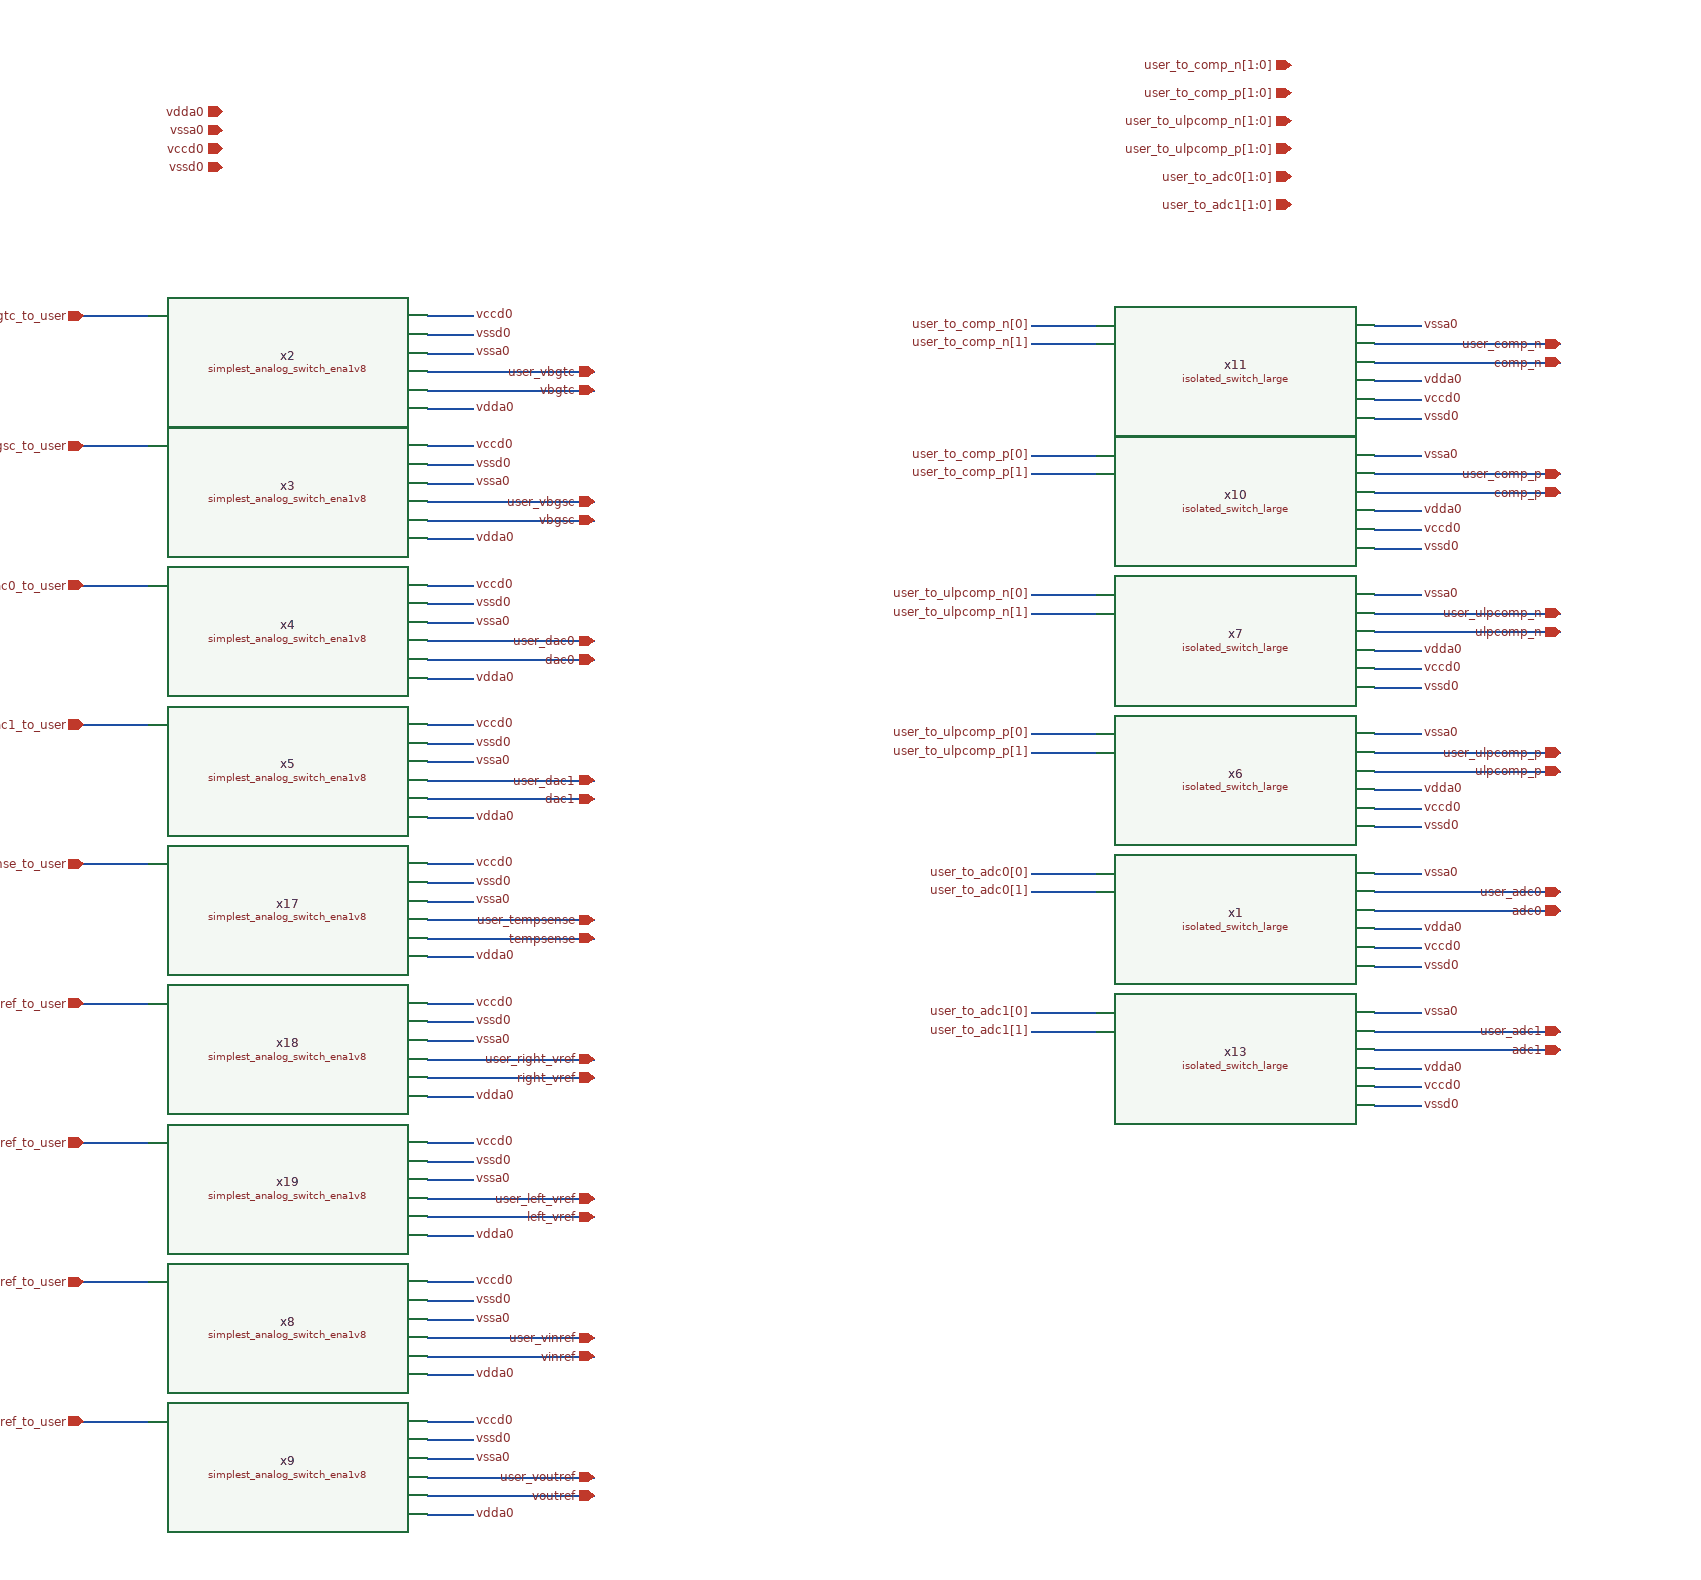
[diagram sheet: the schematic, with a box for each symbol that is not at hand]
v {xschem version=3.4.5 file_version=1.2
}
G {}
K {}
V {}
S {}
E {}
N -210 120 -140 120 {
lab=vbgtc_to_user}
N 160 120 210 120 {
lab=vccd0}
N 160 140 210 140 {
lab=vssd0}
N 160 160 210 160 {
lab=vssa0}
N 160 220 210 220 {
lab=vdda0}
N -210 260 -140 260 {
lab=vbgsc_to_user}
N 160 260 210 260 {
lab=vccd0}
N 160 280 210 280 {
lab=vssd0}
N 160 300 210 300 {
lab=vssa0}
N 160 360 210 360 {
lab=vdda0}
N -210 410 -140 410 {
lab=dac0_to_user}
N 160 410 210 410 {
lab=vccd0}
N 160 430 210 430 {
lab=vssd0}
N 160 450 210 450 {
lab=vssa0}
N 160 510 210 510 {
lab=vdda0}
N 160 180 340 180 {
lab=user_vbgtc}
N 160 320 340 320 {
lab=user_vbgsc}
N 160 470 340 470 {
lab=user_dac0}
N -210 560 -140 560 {
lab=dac1_to_user}
N 160 560 210 560 {
lab=vccd0}
N 160 580 210 580 {
lab=vssd0}
N 160 600 210 600 {
lab=vssa0}
N 160 660 210 660 {
lab=vdda0}
N 160 620 340 620 {
lab=user_dac1}
N 810 720 880 720 {
lab=user_to_adc0[0]}
N -210 1160 -140 1160 {
lab=vinref_to_user}
N 160 1160 210 1160 {
lab=vccd0}
N 160 1180 210 1180 {
lab=vssd0}
N 160 1200 210 1200 {
lab=vssa0}
N 160 1260 210 1260 {
lab=vdda0}
N 160 1220 340 1220 {
lab=user_vinref}
N -210 1310 -140 1310 {
lab=voutref_to_user}
N 160 1310 210 1310 {
lab=vccd0}
N 160 1330 210 1330 {
lab=vssd0}
N 160 1350 210 1350 {
lab=vssa0}
N 160 1410 210 1410 {
lab=vdda0}
N 160 1370 340 1370 {
lab=user_voutref}
N 810 130 880 130 {
lab=user_to_comp_n[0]}
N 1180 210 1230 210 {
lab=vccd0}
N 1180 230 1230 230 {
lab=vssd0}
N 1180 130 1230 130 {
lab=vssa0}
N 810 270 880 270 {
lab=user_to_comp_p[0]}
N 810 420 880 420 {
lab=user_to_ulpcomp_n[0]}
N 810 570 880 570 {
lab=user_to_ulpcomp_p[0]}
N -210 710 -140 710 {
lab=tempsense_to_user}
N 160 710 210 710 {
lab=vccd0}
N 160 730 210 730 {
lab=vssd0}
N 160 750 210 750 {
lab=vssa0}
N 160 810 210 810 {
lab=vdda0}
N 160 770 340 770 {
lab=user_tempsense}
N -210 860 -140 860 {
lab=right_vref_to_user}
N 160 860 210 860 {
lab=vccd0}
N 160 880 210 880 {
lab=vssd0}
N 160 900 210 900 {
lab=vssa0}
N 160 960 210 960 {
lab=vdda0}
N 160 920 340 920 {
lab=user_right_vref}
N -210 1010 -140 1010 {
lab=left_vref_to_user}
N 160 1010 210 1010 {
lab=vccd0}
N 160 1030 210 1030 {
lab=vssd0}
N 160 1050 210 1050 {
lab=vssa0}
N 160 1110 210 1110 {
lab=vdda0}
N 160 1070 340 1070 {
lab=user_left_vref}
N 810 870 880 870 {
lab=user_to_adc1[0]}
N 810 890 880 890 {
lab=user_to_adc1[1]}
N 810 740 880 740 {
lab=user_to_adc0[1]}
N 810 590 880 590 {
lab=user_to_ulpcomp_p[1]}
N 810 440 880 440 {
lab=user_to_ulpcomp_n[1]}
N 810 290 880 290 {
lab=user_to_comp_p[1]}
N 810 150 880 150 {
lab=user_to_comp_n[1]}
N 1180 190 1230 190 {
lab=vdda0}
N 1180 350 1230 350 {
lab=vccd0}
N 1180 370 1230 370 {
lab=vssd0}
N 1180 270 1230 270 {
lab=vssa0}
N 1180 330 1230 330 {
lab=vdda0}
N 1180 500 1230 500 {
lab=vccd0}
N 1180 520 1230 520 {
lab=vssd0}
N 1180 420 1230 420 {
lab=vssa0}
N 1180 480 1230 480 {
lab=vdda0}
N 1180 650 1230 650 {
lab=vccd0}
N 1180 670 1230 670 {
lab=vssd0}
N 1180 570 1230 570 {
lab=vssa0}
N 1180 630 1230 630 {
lab=vdda0}
N 1180 800 1230 800 {
lab=vccd0}
N 1180 820 1230 820 {
lab=vssd0}
N 1180 720 1230 720 {
lab=vssa0}
N 1180 780 1230 780 {
lab=vdda0}
N 1180 950 1230 950 {
lab=vccd0}
N 1180 970 1230 970 {
lab=vssd0}
N 1180 870 1230 870 {
lab=vssa0}
N 1180 930 1230 930 {
lab=vdda0}
N 160 1390 340 1390 {
lab=voutref}
N 160 1240 340 1240 {
lab=vinref}
N 160 1090 340 1090 {
lab=left_vref}
N 160 940 340 940 {
lab=right_vref}
N 160 790 340 790 {
lab=tempsense}
N 160 640 340 640 {
lab=dac1}
N 160 490 340 490 {
lab=dac0}
N 160 340 340 340 {
lab=vbgsc}
N 160 200 340 200 {
lab=vbgtc}
N 1180 460 1380 460 {
lab=ulpcomp_n}
N 1180 610 1380 610 {
lab=ulpcomp_p}
N 1180 760 1380 760 {
lab=adc0}
N 1180 910 1380 910 {
lab=adc1}
N 1180 310 1380 310 {
lab=comp_p}
N 1180 170 1380 170 {
lab=comp_n}
N 1180 890 1380 890 {
lab=user_adc1}
N 1180 740 1380 740 {
lab=user_adc0}
N 1180 590 1380 590 {
lab=user_ulpcomp_p}
N 1180 440 1380 440 {
lab=user_ulpcomp_n}
N 1180 290 1380 290 {
lab=user_comp_p}
N 1180 150 1380 150 {
lab=user_comp_n}
C {devices/iopin.sym} -60 -60 0 0 {name=p1 lab=vccd0}
C {devices/iopin.sym} -60 -100 0 0 {name=p3 lab=vdda0}
C {devices/iopin.sym} -60 -80 0 0 {name=p4 lab=vssa0}
C {devices/iopin.sym} -60 -40 0 0 {name=p5 lab=vssd0}
C {simplest_analog_switch_ena1v8.sym} 10 170 0 0 {name=x2}
C {devices/ipin.sym} -210 120 0 0 {name=p10 lab=vbgtc_to_user}
C {devices/lab_pin.sym} 210 120 0 1 {name=p11 sig_type=std_logic lab=vccd0}
C {devices/lab_pin.sym} 210 140 0 1 {name=p12 sig_type=std_logic lab=vssd0}
C {devices/lab_pin.sym} 210 160 0 1 {name=p13 sig_type=std_logic lab=vssa0}
C {devices/lab_pin.sym} 210 220 0 1 {name=p14 sig_type=std_logic lab=vdda0}
C {simplest_analog_switch_ena1v8.sym} 10 310 0 0 {name=x3}
C {devices/ipin.sym} -210 260 0 0 {name=p15 lab=vbgsc_to_user}
C {devices/lab_pin.sym} 210 260 0 1 {name=p16 sig_type=std_logic lab=vccd0}
C {devices/lab_pin.sym} 210 280 0 1 {name=p17 sig_type=std_logic lab=vssd0}
C {devices/lab_pin.sym} 210 300 0 1 {name=p18 sig_type=std_logic lab=vssa0}
C {devices/lab_pin.sym} 210 360 0 1 {name=p19 sig_type=std_logic lab=vdda0}
C {simplest_analog_switch_ena1v8.sym} 10 460 0 0 {name=x4}
C {devices/ipin.sym} -210 410 0 0 {name=p20 lab=dac0_to_user}
C {devices/lab_pin.sym} 210 410 0 1 {name=p21 sig_type=std_logic lab=vccd0}
C {devices/lab_pin.sym} 210 430 0 1 {name=p22 sig_type=std_logic lab=vssd0}
C {devices/lab_pin.sym} 210 450 0 1 {name=p23 sig_type=std_logic lab=vssa0}
C {devices/lab_pin.sym} 210 510 0 1 {name=p24 sig_type=std_logic lab=vdda0}
C {simplest_analog_switch_ena1v8.sym} 10 610 0 0 {name=x5}
C {devices/ipin.sym} -210 560 0 0 {name=p25 lab=dac1_to_user}
C {devices/lab_pin.sym} 210 560 0 1 {name=p26 sig_type=std_logic lab=vccd0}
C {devices/lab_pin.sym} 210 580 0 1 {name=p27 sig_type=std_logic lab=vssd0}
C {devices/lab_pin.sym} 210 600 0 1 {name=p28 sig_type=std_logic lab=vssa0}
C {devices/lab_pin.sym} 210 660 0 1 {name=p29 sig_type=std_logic lab=vdda0}
C {simplest_analog_switch_ena1v8.sym} 10 1210 0 0 {name=x8}
C {devices/ipin.sym} -210 1160 0 0 {name=p40 lab=vinref_to_user}
C {devices/lab_pin.sym} 210 1160 0 1 {name=p41 sig_type=std_logic lab=vccd0}
C {devices/lab_pin.sym} 210 1180 0 1 {name=p42 sig_type=std_logic lab=vssd0}
C {devices/lab_pin.sym} 210 1200 0 1 {name=p43 sig_type=std_logic lab=vssa0}
C {devices/lab_pin.sym} 210 1260 0 1 {name=p44 sig_type=std_logic lab=vdda0}
C {simplest_analog_switch_ena1v8.sym} 10 1360 0 0 {name=x9}
C {devices/ipin.sym} -210 1310 0 0 {name=p45 lab=voutref_to_user}
C {devices/lab_pin.sym} 210 1310 0 1 {name=p46 sig_type=std_logic lab=vccd0}
C {devices/lab_pin.sym} 210 1330 0 1 {name=p47 sig_type=std_logic lab=vssd0}
C {devices/lab_pin.sym} 210 1350 0 1 {name=p48 sig_type=std_logic lab=vssa0}
C {devices/lab_pin.sym} 210 1410 0 1 {name=p49 sig_type=std_logic lab=vdda0}
C {devices/lab_pin.sym} 1230 210 0 1 {name=p62 sig_type=std_logic lab=vccd0}
C {devices/lab_pin.sym} 1230 230 0 1 {name=p63 sig_type=std_logic lab=vssd0}
C {devices/lab_pin.sym} 1230 130 0 1 {name=p64 sig_type=std_logic lab=vssa0}
C {simplest_analog_switch_ena1v8.sym} 10 760 0 0 {name=x17}
C {devices/ipin.sym} -210 710 0 0 {name=p86 lab=tempsense_to_user}
C {devices/lab_pin.sym} 210 710 0 1 {name=p87 sig_type=std_logic lab=vccd0}
C {devices/lab_pin.sym} 210 730 0 1 {name=p88 sig_type=std_logic lab=vssd0}
C {devices/lab_pin.sym} 210 750 0 1 {name=p89 sig_type=std_logic lab=vssa0}
C {devices/lab_pin.sym} 210 810 0 1 {name=p90 sig_type=std_logic lab=vdda0}
C {simplest_analog_switch_ena1v8.sym} 10 910 0 0 {name=x18}
C {devices/ipin.sym} -210 860 0 0 {name=p91 lab=right_vref_to_user}
C {devices/lab_pin.sym} 210 860 0 1 {name=p92 sig_type=std_logic lab=vccd0}
C {devices/lab_pin.sym} 210 880 0 1 {name=p93 sig_type=std_logic lab=vssd0}
C {devices/lab_pin.sym} 210 900 0 1 {name=p94 sig_type=std_logic lab=vssa0}
C {devices/lab_pin.sym} 210 960 0 1 {name=p95 sig_type=std_logic lab=vdda0}
C {simplest_analog_switch_ena1v8.sym} 10 1060 0 0 {name=x19}
C {devices/ipin.sym} -210 1010 0 0 {name=p96 lab=left_vref_to_user}
C {devices/lab_pin.sym} 210 1010 0 1 {name=p97 sig_type=std_logic lab=vccd0}
C {devices/lab_pin.sym} 210 1030 0 1 {name=p98 sig_type=std_logic lab=vssd0}
C {devices/lab_pin.sym} 210 1050 0 1 {name=p99 sig_type=std_logic lab=vssa0}
C {devices/lab_pin.sym} 210 1110 0 1 {name=p100 sig_type=std_logic lab=vdda0}
C {devices/iopin.sym} 1380 610 0 0 {name=p181 lab=ulpcomp_p}
C {devices/iopin.sym} 1380 460 0 0 {name=p182 lab=ulpcomp_n}
C {devices/iopin.sym} 1380 310 0 0 {name=p183 lab=comp_p}
C {devices/iopin.sym} 1380 170 0 0 {name=p184 lab=comp_n}
C {devices/iopin.sym} 1380 760 0 0 {name=p185 lab=adc0}
C {devices/iopin.sym} 1380 910 0 0 {name=p186 lab=adc1}
C {devices/iopin.sym} 340 490 0 0 {name=p187 lab=dac0}
C {devices/iopin.sym} 340 640 0 0 {name=p188 lab=dac1}
C {devices/lab_pin.sym} 810 130 0 0 {name=p31 sig_type=std_logic lab=user_to_comp_n[0]}
C {devices/lab_pin.sym} 810 150 0 0 {name=p32 sig_type=std_logic lab=user_to_comp_n[1]}
C {devices/lab_pin.sym} 810 270 0 0 {name=p33 sig_type=std_logic lab=user_to_comp_p[0]}
C {devices/lab_pin.sym} 810 290 0 0 {name=p34 sig_type=std_logic lab=user_to_comp_p[1]}
C {devices/lab_pin.sym} 810 420 0 0 {name=p35 sig_type=std_logic lab=user_to_ulpcomp_n[0]}
C {devices/lab_pin.sym} 810 440 0 0 {name=p50 sig_type=std_logic lab=user_to_ulpcomp_n[1]}
C {devices/lab_pin.sym} 810 570 0 0 {name=p51 sig_type=std_logic lab=user_to_ulpcomp_p[0]}
C {devices/lab_pin.sym} 810 590 0 0 {name=p52 sig_type=std_logic lab=user_to_ulpcomp_p[1]}
C {devices/lab_pin.sym} 810 720 0 0 {name=p53 sig_type=std_logic lab=user_to_adc0[0]}
C {devices/lab_pin.sym} 810 740 0 0 {name=p54 sig_type=std_logic lab=user_to_adc0[1]}
C {devices/lab_pin.sym} 810 870 0 0 {name=p55 sig_type=std_logic lab=user_to_adc1[0]}
C {devices/lab_pin.sym} 810 890 0 0 {name=p56 sig_type=std_logic lab=user_to_adc1[1]}
C {devices/lab_pin.sym} 1230 190 0 1 {name=p36 sig_type=std_logic lab=vdda0}
C {devices/lab_pin.sym} 1230 350 0 1 {name=p37 sig_type=std_logic lab=vccd0}
C {devices/lab_pin.sym} 1230 370 0 1 {name=p38 sig_type=std_logic lab=vssd0}
C {devices/lab_pin.sym} 1230 270 0 1 {name=p39 sig_type=std_logic lab=vssa0}
C {devices/lab_pin.sym} 1230 330 0 1 {name=p58 sig_type=std_logic lab=vdda0}
C {devices/lab_pin.sym} 1230 500 0 1 {name=p59 sig_type=std_logic lab=vccd0}
C {devices/lab_pin.sym} 1230 520 0 1 {name=p60 sig_type=std_logic lab=vssd0}
C {devices/lab_pin.sym} 1230 420 0 1 {name=p61 sig_type=std_logic lab=vssa0}
C {devices/lab_pin.sym} 1230 480 0 1 {name=p65 sig_type=std_logic lab=vdda0}
C {devices/lab_pin.sym} 1230 650 0 1 {name=p66 sig_type=std_logic lab=vccd0}
C {devices/lab_pin.sym} 1230 670 0 1 {name=p67 sig_type=std_logic lab=vssd0}
C {devices/lab_pin.sym} 1230 570 0 1 {name=p68 sig_type=std_logic lab=vssa0}
C {devices/lab_pin.sym} 1230 630 0 1 {name=p69 sig_type=std_logic lab=vdda0}
C {devices/lab_pin.sym} 1230 800 0 1 {name=p70 sig_type=std_logic lab=vccd0}
C {devices/lab_pin.sym} 1230 820 0 1 {name=p71 sig_type=std_logic lab=vssd0}
C {devices/lab_pin.sym} 1230 720 0 1 {name=p72 sig_type=std_logic lab=vssa0}
C {devices/lab_pin.sym} 1230 780 0 1 {name=p73 sig_type=std_logic lab=vdda0}
C {devices/lab_pin.sym} 1230 950 0 1 {name=p74 sig_type=std_logic lab=vccd0}
C {devices/lab_pin.sym} 1230 970 0 1 {name=p75 sig_type=std_logic lab=vssd0}
C {devices/lab_pin.sym} 1230 870 0 1 {name=p76 sig_type=std_logic lab=vssa0}
C {devices/lab_pin.sym} 1230 930 0 1 {name=p77 sig_type=std_logic lab=vdda0}
C {devices/iopin.sym} 340 790 0 0 {name=p57 lab=tempsense}
C {devices/iopin.sym} 340 940 0 0 {name=p78 lab=right_vref}
C {devices/iopin.sym} 340 1090 0 0 {name=p79 lab=left_vref}
C {devices/iopin.sym} 340 1240 0 0 {name=p80 lab=vinref}
C {devices/iopin.sym} 340 1390 0 0 {name=p81 lab=voutref}
C {devices/iopin.sym} 340 340 0 0 {name=p103 lab=vbgsc}
C {devices/iopin.sym} 340 200 0 0 {name=p104 lab=vbgtc}
C {devices/iopin.sym} 340 180 0 0 {name=p82 lab=user_vbgtc}
C {devices/iopin.sym} 340 320 0 0 {name=p83 lab=user_vbgsc}
C {devices/iopin.sym} 340 470 0 0 {name=p84 lab=user_dac0}
C {devices/iopin.sym} 340 620 0 0 {name=p85 lab=user_dac1}
C {devices/iopin.sym} 340 770 0 0 {name=p101 lab=user_tempsense}
C {devices/iopin.sym} 340 920 0 0 {name=p102 lab=user_right_vref}
C {devices/iopin.sym} 340 1070 0 0 {name=p105 lab=user_left_vref}
C {devices/iopin.sym} 340 1220 0 0 {name=p106 lab=user_vinref}
C {devices/iopin.sym} 340 1370 0 0 {name=p107 lab=user_voutref}
C {devices/iopin.sym} 1380 890 0 0 {name=p108 lab=user_adc1}
C {devices/iopin.sym} 1380 740 0 0 {name=p109 lab=user_adc0}
C {devices/iopin.sym} 1380 590 0 0 {name=p110 lab=user_ulpcomp_p}
C {devices/iopin.sym} 1380 440 0 0 {name=p111 lab=user_ulpcomp_n}
C {devices/iopin.sym} 1380 290 0 0 {name=p112 lab=user_comp_p}
C {devices/iopin.sym} 1380 150 0 0 {name=p113 lab=user_comp_n}
C {devices/ipin.sym} 1090 -150 0 0 {name=p114 lab=user_to_comp_n[1:0]}
C {devices/ipin.sym} 1090 -120 0 0 {name=p115 lab=user_to_comp_p[1:0]}
C {devices/ipin.sym} 1090 -90 0 0 {name=p116 lab=user_to_ulpcomp_n[1:0]}
C {devices/ipin.sym} 1090 -60 0 0 {name=p117 lab=user_to_ulpcomp_p[1:0]}
C {devices/ipin.sym} 1090 -30 0 0 {name=p118 lab=user_to_adc0[1:0]}
C {devices/ipin.sym} 1090 0 0 0 {name=p119 lab=user_to_adc1[1:0]}
C {isolated_switch_large.sym} 1030 920 0 0 {name=x13}
C {isolated_switch_large.sym} 1030 770 0 0 {name=x1}
C {isolated_switch_large.sym} 1030 620 0 0 {name=x6}
C {isolated_switch_large.sym} 1030 470 0 0 {name=x7}
C {isolated_switch_large.sym} 1030 320 0 0 {name=x10}
C {isolated_switch_large.sym} 1030 180 0 0 {name=x11}
